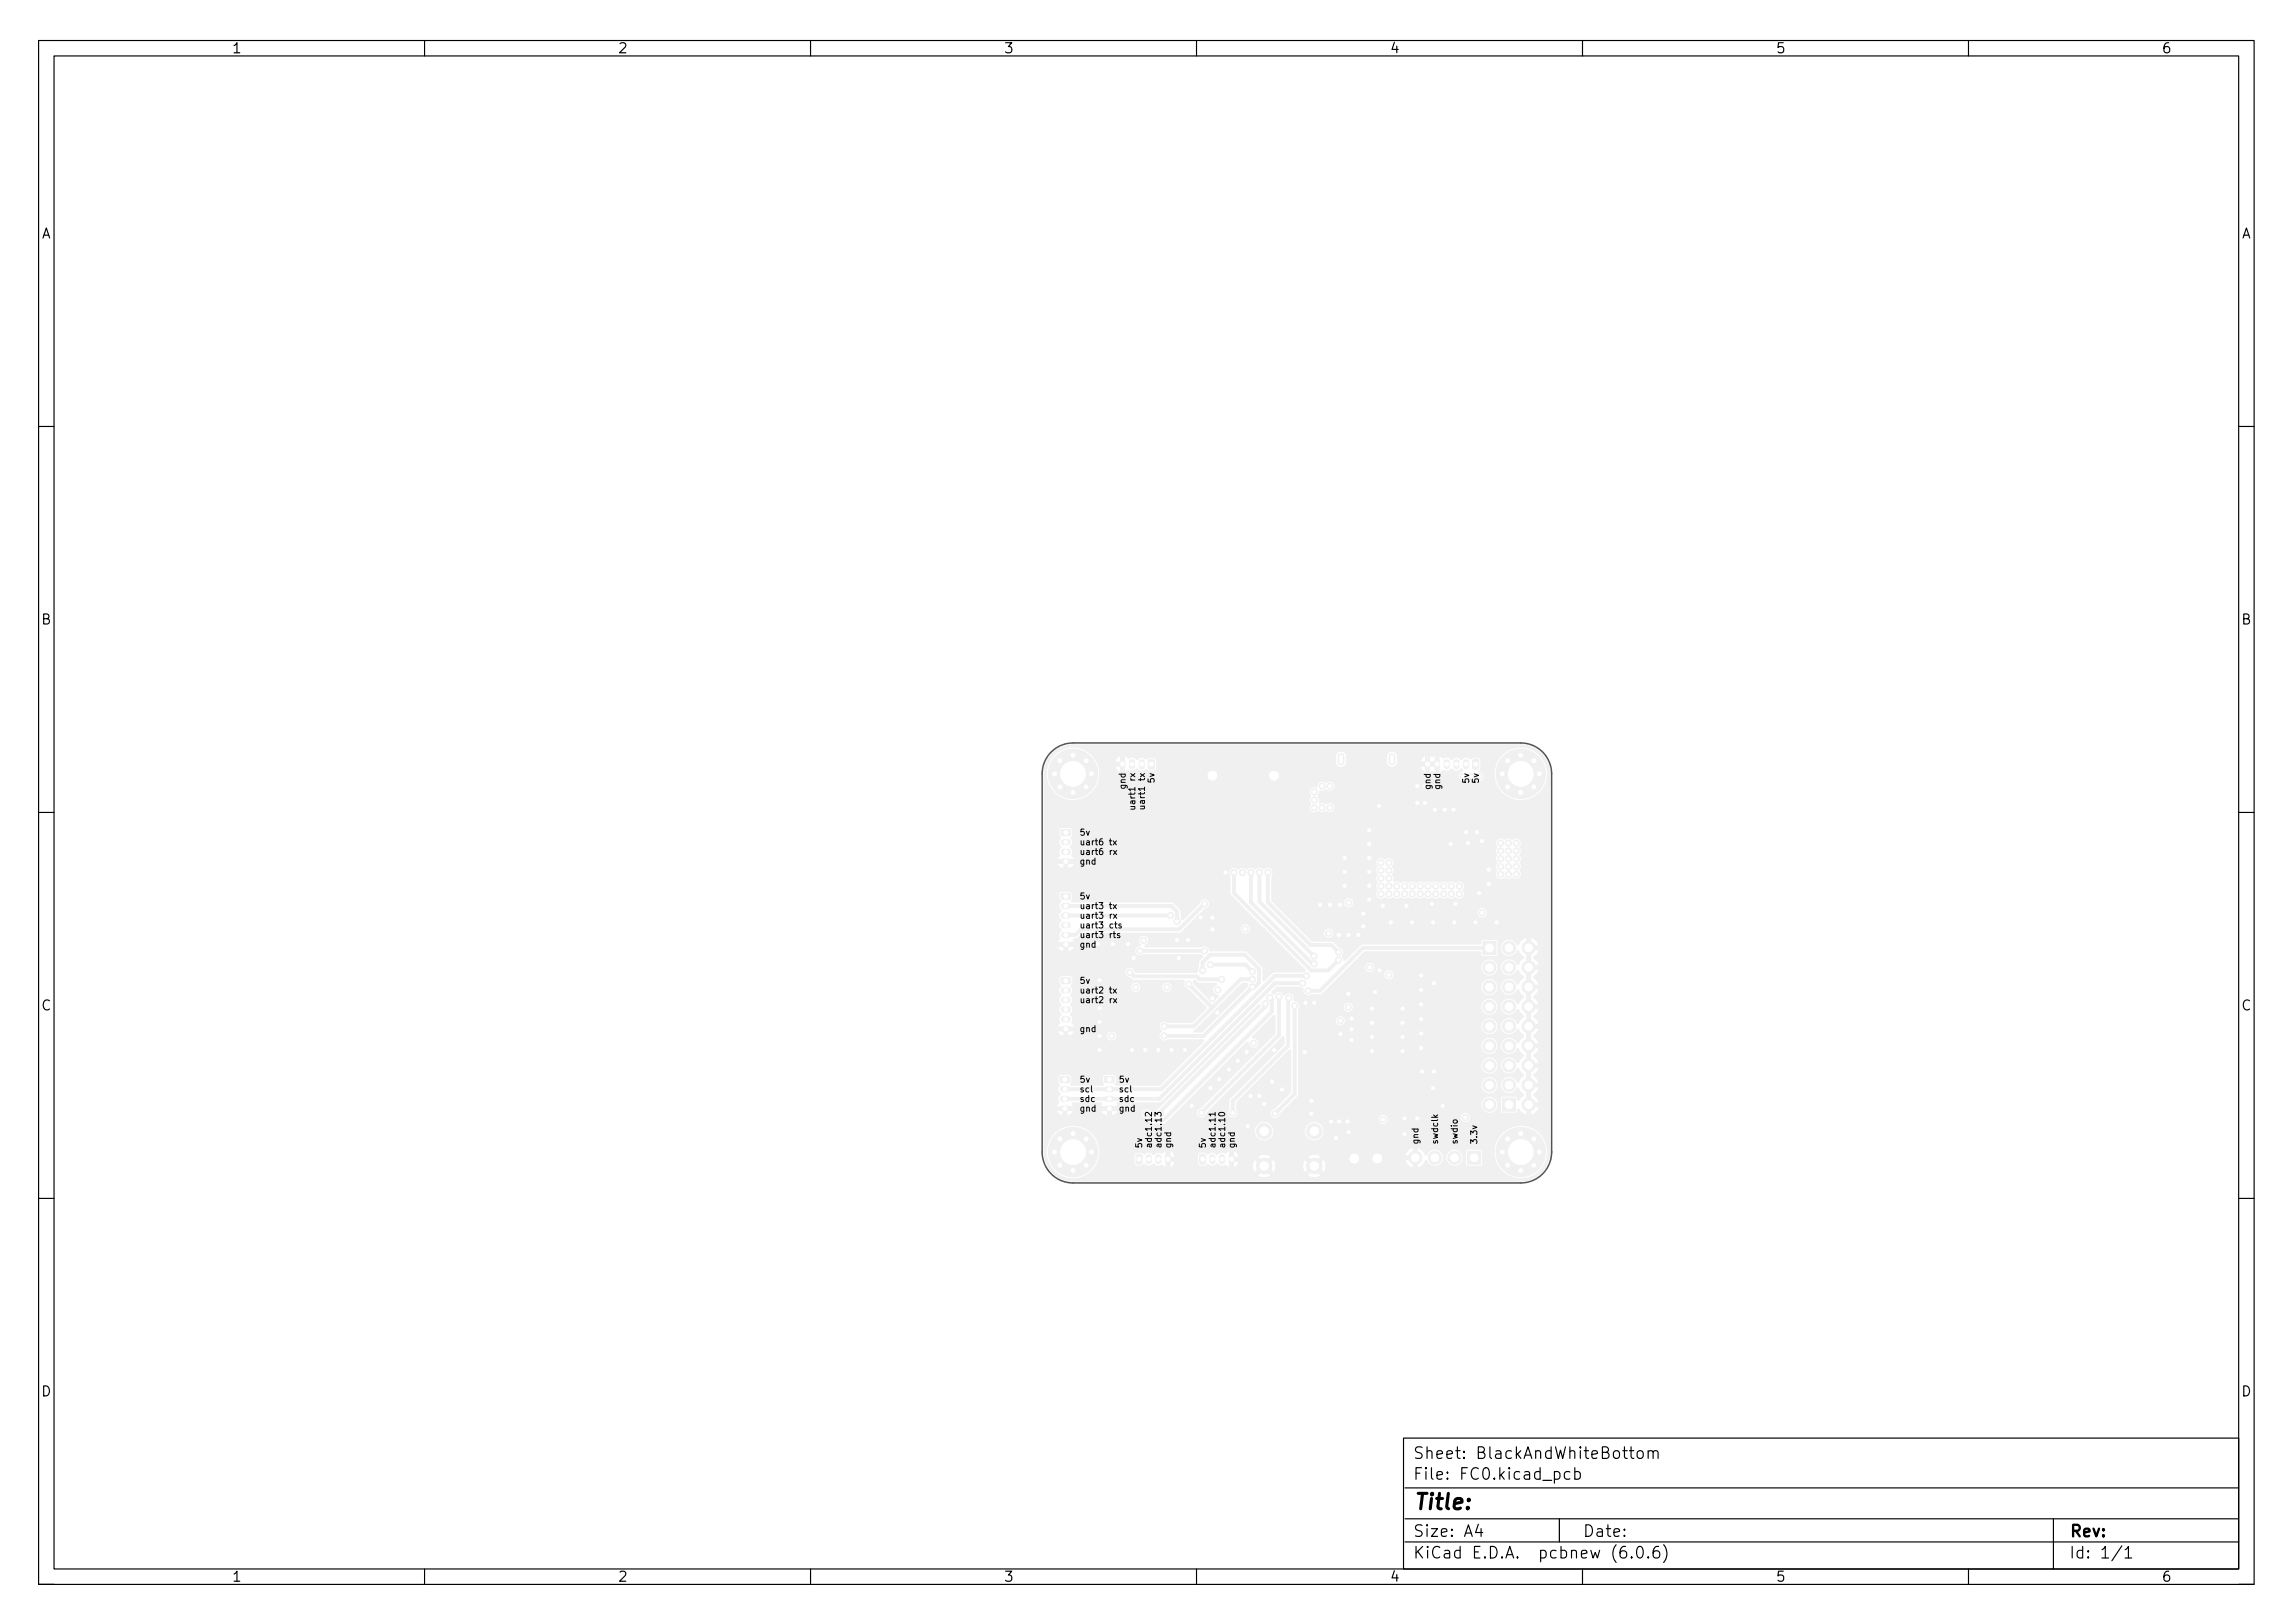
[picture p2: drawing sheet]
<svg xmlns="http://www.w3.org/2000/svg" width="297mm" height="210mm" viewBox="0 0 297 210" stroke-linecap="round" stroke-linejoin="round" font-family="sans-serif">
<defs><g id="words">
<text font-size="2.8" x="183" y="195.6">Title:</text>
<g font-size="2.1">
<text x="183" y="191.7">File: FC0.kicad_pcb</text>
<text x="183" y="189">Sheet: BlackAndWhiteBottom</text>
<text x="183" y="201.9">KiCad E.D.A. pcbnew (6.0.6)</text>
<text x="183" y="199.1">Size: A4</text>
<text x="205" y="199.1">Date:</text>
<text x="268" y="199.1">Rev:</text>
<text x="268" y="201.9">Id: 1/1</text>
</g>
<g font-size="1.8">
<text x="30" y="6.9">1</text>
<text x="80" y="6.9">2</text>
<text x="130" y="6.9">3</text>
<text x="180" y="6.9">4</text>
<text x="230" y="6.9">5</text>
<text x="280" y="6.9">6</text>
<text x="5.3" y="30.9">A</text>
<text x="290.3" y="30.9">A</text>
<text x="5.3" y="80.9">B</text>
<text x="290.3" y="80.9">B</text>
<text x="5.3" y="130.9">C</text>
<text x="290.3" y="130.9">C</text>
<text x="5.3" y="180.9">D</text>
<text x="290.3" y="180.9">D</text>
<text x="30" y="204.9">1</text>
<text x="80" y="204.9">2</text>
<text x="130" y="204.9">3</text>
<text x="180" y="204.9">4</text>
<text x="230" y="204.9">5</text>
<text x="280" y="204.9">6</text>
</g>
<g font-size="1.1">
<text x="149.6" y="101.6" transform="rotate(-90 149.6 101.6)">5v</text>
<text x="190.3" y="101.6" transform="rotate(-90 190.3 101.6)">5v</text>
<text x="191.6" y="101.6" transform="rotate(-90 191.6 101.6)">5v</text>
<text x="145.8" y="102.4" transform="rotate(-90 145.8 102.4)">gnd</text>
<text x="147.1" y="105.1" transform="rotate(-90 147.1 105.1)">uart1 rx</text>
<text x="148.3" y="105.1" transform="rotate(-90 148.3 105.1)">uart1 tx</text>
<text x="185.3" y="102.4" transform="rotate(-90 185.3 102.4)">gnd</text>
<text x="186.6" y="102.4" transform="rotate(-90 186.6 102.4)">gnd</text>
<text x="139.8" y="109.5">uart6 tx</text>
<text x="139.8" y="108.2">5v</text>
<text x="139.8" y="112">gnd</text>
<text x="139.8" y="110.7">uart6 rx</text>
<text x="139.8" y="119">uart3 rx</text>
<text x="139.8" y="117.8">uart3 tx</text>
<text x="139.8" y="116.5">5v</text>
<text x="139.8" y="120.3">uart3 cts</text>
<text x="139.8" y="121.5">uart3 rts</text>
<text x="139.8" y="122.8">gnd</text>
<text x="139.8" y="128.7">uart2 tx</text>
<text x="139.8" y="127.4">5v</text>
<text x="139.8" y="129.9">uart2 rx</text>
<text x="139.8" y="133.7">gnd</text>
<text x="139.8" y="140.3">5v</text>
<text x="139.8" y="141.5">scl</text>
<text x="139.8" y="142.8">sdc</text>
<text x="144.9" y="142.8">sdc</text>
<text x="144.9" y="141.5">scl</text>
<text x="144.9" y="140.3">5v</text>
<text x="139.8" y="144">gnd</text>
<text x="144.9" y="144">gnd</text>
<text x="148" y="148.8" transform="rotate(-90 148 148.8)">5v</text>
<text x="149.2" y="148.8" transform="rotate(-90 149.2 148.8)">adc1.12</text>
<text x="150.5" y="148.8" transform="rotate(-90 150.5 148.8)">adc1.13</text>
<text x="151.7" y="148.8" transform="rotate(-90 151.7 148.8)">gnd</text>
<text x="156.2" y="148.8" transform="rotate(-90 156.2 148.8)">5v</text>
<text x="157.4" y="148.8" transform="rotate(-90 157.4 148.8)">adc1.11</text>
<text x="158.7" y="148.8" transform="rotate(-90 158.7 148.8)">adc1.10</text>
<text x="159.9" y="148.8" transform="rotate(-90 159.9 148.8)">gnd</text>
<text x="183.7" y="148.3" transform="rotate(-90 183.7 148.3)">gnd</text>
<text x="186.3" y="148.3" transform="rotate(-90 186.3 148.3)">swdclk</text>
<text x="188.8" y="148.3" transform="rotate(-90 188.8 148.3)">swdio</text>
<text x="191.4" y="148.3" transform="rotate(-90 191.4 148.3)">3.3v</text>
</g>
</g></defs>
<g fill="none" stroke="#000" stroke-width=".15">
<path d="M5 5.2h287v200.1h-287zM7 7.2h283v196.1h-283zM55 5.2v2M105 5.2v2M155 5.2v2M205 5.2v2M255 5.2v2M5 55.2h2M290 55.2h2M5 105.2h2M290 105.2h2M5 155.2h2"/>
<path d="M290 155.2h2M181.8 186.3h108.2v17h-108.2zM182 199.8h108M182 196.8h108M182 192.8h108M191.5 197.5l-.4 1h1M191.9 198v1M202 196.8v3M203.4 190.7l-.5-.1-.3 .3v.4l.2 .3h.1h.5M204 190.7l.4-.1 .3 .3v.4l-.1 .3h-.2h-.4M204 190.1v1.5M211.1 187.9h.5"/>
<path d="M211.3 187.4v1.3l.1 .2h.2M212.2 188a.41 .41 0 0 1 .7 .2v.4a.41 .41 0 0 1-.4 .3 .41 .41 0 0 1-.4-.3v-.4zM213.5 188.1a.37 .37 0 0 1 .6 0v.8M213.5 187.9v1M214.1 188.1l.3-.2 .3 .1 .1 .9M266 196.8v6.5M5 205.2h2M55 203.3v2M105 203.3v2M155 203.3v2M205 203.3v2M211.4 201.7v.1h-.1l.1-.1v.1"/>
<path d="M212.2 200.4a.36 .36 0 0 1 .6 .2 .77 .77 0 0 1-.4 1.2 1 1 0 0 1-.2-1.4zM213.5 201.7l.1 .1h-.1h-.1l.1-.1v.1M214.9 200.3a.59 .59 0 0 0-.8 .7v.5l.2 .3h.4l.2-.1 .1-.5-.1-.2-.5-.1-.3 .3M215.5 200.1a1.72 1.72 0 0 1 0 2.3M255 203.3v2M274.9 200.3l-1.3 1.9M275.3 200.8l.4-.5v1.5M275.3 201.8h.8M290 205.2h2"/>
</g>
<g fill="#f0f0f0" stroke="#f0f0f0" stroke-width=".13">
<path d="M147.2 149.6l.6-.1 .1 .1 .1 1-.2 .2h-.4l-.2-.1z"/>
<path d="M155.5 149.6l.5-.1 .2 .1v1l-.1 .2h-.5l-.2-.1z"/>
<path d="M143.1 139.5h1.1l.2 .2-.1 .4-.1 .2-1-.1-.1-.1z"/>
<path d="M137.3 139.5h1.2l.1 .2v.4l-.2 .2-1-.1-.1-.1z"/>
<path d="M137.5 115.8l1.1-.1 .1 .2v.5l-.2 .1h-1l-.1-.2z"/>
<path d="M148.8 98.4l.6-.1 .1 .2 .1 .9-.2 .2h-.4l-.2-.1z"/>
<path d="M194.6 142.3h1.7v1.7h-1.7z"/>
<path d="M137.5 107.5h1.1l.1 .1v.5l-.2 .1h-1l-.1-.2z"/>
<path d="M137.5 126.7h1.1l.1 .1v.5l-.2 .1h-1l-.1-.2z"/>
<path d="M190.1 149.1h1.7v1.7h-1.7z"/>
<path d="M190.8 98.4l.6-.1 .1 .2 .1 .9-.2 .2h-.4l-.2-.1z"/>
<path d="M192.1 122h1.7v1.7h-1.7z"/>
<path d="M136.3 97.6a3.7 3.7 0 0 1 2.7-1.1h58a3.7 3.7 0 0 1 3.7 3.7h-.2l-.1-.7a3.5 3.5 0 0 0-3.9-2.7 3.5 3.5 0 0 0-2.9 3.8h-1.4a.75 .75 0 0 0-.5-.7l.1-.4v-1a.71 .71 0 0 0-.9-.4l-.3 .1a.28 .28 0 0 1-.4-.1 .72 .72 0 0 0-.9 .3 .79 .79 0 0 0-1.2 0 .84 .84 0 0 0-1-.2h-.2l-.5-.3v.8h-.5v-.8l-.4 .1-.3-.1v.8h-.5l-.1-.8a.9 .9 0 0 0-.6 .8l2.4 .1h-5.4v-.8a.71 .71 0 0 0-.7-.7 .71 .71 0 0 0-.7 .7v.8h-5.2v-.8a.71 .71 0 0 0-.7-.7 .71 .71 0 0 0-.7 .7v.5h-23.2a.68 .68 0 0 0-.9-.4l-.3 .1a.27 .27 0 0 1-.4-.1h-.5l-.5 .3-.4-.3-.6 .1-.5-.3v.8h-.5l-.1-.8a.9 .9 0 0 0-.6 .8h1.2v1.4h-.5l-.1-.8h-.6a.89 .89 0 0 0 .6 .8h.6l.3-.2a.33 .33 0 0 1 .5 0 .74 .74 0 0 0 .8-.3 .89 .89 0 0 0 1.2 .1h.1a.82 .82 0 0 0 .8 .2l.3-.1 .1-.3v-1h23.2a.74 .74 0 0 0 .8 .9l.4-.2 .2-.4h5.2a.71 .71 0 0 0 .7 .6 .71 .71 0 0 0 .7-.6h5.4v1.3h-.5v-.8h-.7v.8h-.5v-.8h-.7a.89 .89 0 0 0 .6 .8h.6l.3-.2 .4 .2 .7-.1a.37 .37 0 0 1 .5-.2l.1 .1a.72 .72 0 0 0 .8-.3 .81 .81 0 0 0 1.3 0l.2 .2-.4 .3-.2 .5h-23.1l-.2-.5a.71 .71 0 0 0-.8-.3 .71 .71 0 0 0-.5 .8h-6.5l-.2-.5a.71 .71 0 0 0-1.2 .1h-13.9l-.1-.7a3.5 3.5 0 0 0-5.6-2 3.5 3.5 0 0 0 .7 5.9 3.5 3.5 0 0 0 5-3.2l13.9 .1a.71 .71 0 0 0 .8 .9 .71 .71 0 0 0 .6-.6h6.5l.2 .3a.71 .71 0 0 0 .7 .3 .71 .71 0 0 0 .6-.6h23.1a.69 .69 0 0 0 .4 .6 .69 .69 0 0 0 .8-.2l.1 .1a.77 .77 0 0 0 .9-.1 .67 .67 0 0 0 .7 .2 .67 .67 0 0 0 .5-.6h1.3l.1 .8 .3 .6a3.5 3.5 0 0 0 3.9 1.6 3.5 3.5 0 0 0 2.6-3.4h.2v4.4h-27.8a.71 .71 0 0 0-.4-.6 .71 .71 0 0 0-.7 .2l-.5-.2h-.4v-.5l-.2-.4 .2-.6h.5l.4-.2a.68 .68 0 0 0 1 0 .68 .68 0 0 0-.1-1 .68 .68 0 0 0-.9 .1 .7 .7 0 0 0-.8-.1 .7 .7 0 0 0-.4 .6l-.1 .1a.69 .69 0 0 0-.8 .3 .69 .69 0 0 0 .1 .8v.1a.78 .78 0 0 0 0 1 .68 .68 0 0 0 0 .9 .68 .68 0 0 0 1 0l.1 .1a.77 .77 0 0 0 .9-.1 .68 .68 0 0 0 .7 .2 .68 .68 0 0 0 .4-.7h27.8v8.7h-3.6l-.2-.5 .2-.5-.2-.6 .2-.3-.1-.5a.4 .4 0 0 1 .1-.5v-.3l-.2-.3a.73 .73 0 0 0 .1-.8 .73 .73 0 0 0-.7-.4l-.4 .1-.4-.1-.6 .1a.74 .74 0 0 0-1.2 .5v.2a.45 .45 0 0 1 0 .7l.2 .7a.77 .77 0 0 0 0 1 .78 .78 0 0 0 0 1 .68 .68 0 0 0 .1 1 .68 .68 0 0 0 .9-.1l.1 .1a.77 .77 0 0 0 .9-.1 .67 .67 0 0 0 .8 .2 .67 .67 0 0 0 .4-.6h3.6v2.5h-11l-.1-.3a.4 .4 0 0 1 .1-.5 .7 .7 0 0 0-.4-.8 .7 .7 0 0 0-.8 .1 .74 .74 0 0 0-1 0h-.1a.74 .74 0 0 0-.9 0h-.1a.74 .74 0 0 0-.9 0h-.1a.74 .74 0 0 0-.9 0h-.1a.74 .74 0 0 0-1 0 .74 .74 0 0 0-1 0 .74 .74 0 0 0-1 0l-.2-.1h-.6l-.1-.1a.88 .88 0 0 0-.1-.8l.2-.5-.2-.6a.68 .68 0 0 0-.1-1 .68 .68 0 0 0-.9 .1 .7 .7 0 0 0-1 0h-39.2l-.4-.5a.74 .74 0 0 0-.1-1 .9 .9 0 0 0 0-1.3l.3-.4v-.5l-.2-.3-.2-.1h-1.1l-.2 .1-.1 .3v.5l.1 .3a.27 .27 0 0 1-.1 .4 .76 .76 0 0 0 .3 .9l-.2 .2a.85 .85 0 0 0 0 .9l-.4 .5h41.5l-.1 .3-.1 .3h-39.9v.6h-.5v-.6h-.9a.9 .9 0 0 0 .9 .6h.5a.89 .89 0 0 0 .9-.6h39.1a.45 .45 0 0 1 0 .7v.3l.1 .3a.9 .9 0 0 0 0 1.1v.1a1.25 1.25 0 0 0 0 1 .68 .68 0 0 0 .1 .9 .68 .68 0 0 0 .9 0l.2 .1a.77 .77 0 0 0 .8-.1l.2 .1a.77 .77 0 0 0 .8-.1l.2 .1a.77 .77 0 0 0 .9-.1l.1 .1a.77 .77 0 0 0 .9-.1l.1 .1a.77 .77 0 0 0 .9-.1l.1 .1a.77 .77 0 0 0 .9-.1l.1 .1a.77 .77 0 0 0 .9-.1l.2 .1a.77 .77 0 0 0 .8-.1l.2 .1a.77 .77 0 0 0 .9-.1 .67 .67 0 0 0 .7 .1 .67 .67 0 0 0 .4-.6h11v1.1h-25.3a.66 .66 0 0 0-1-.6 .66 .66 0 0 0 0 1.2 .66 .66 0 0 0 1-.5l25.3-.1v1.3h-8a.66 .66 0 0 0-1-.5 .66 .66 0 0 0-.1 1.1 .66 .66 0 0 0 1-.4l.1-.2h8v2.7h-27.9a.66 .66 0 0 0-1-.6 .66 .66 0 0 0-.1 1.1 .66 .66 0 0 0 1.1-.4v-.1h27.9v1.6h-1.3l-.1-.2a1.26 1.26 0 0 0-1-.8v1h2.4v2.6h-1.3l-.3-.6-.4-.4 .4-.5 .3-.6-1.1 .1v2h2.4v2.5h-1.3l-.3-.6-.4-.4 .4-.5 .3-.5h-1.1v2h2.4v2.5h-1.3l-.3-.5-.4-.5 .4-.4 .3-.6h-1.1v2h2.4v2.6h-1.3l-.3-.6-.4-.4 .4-.5 .3-.5h-1.1v2h2.4v2.5h-1.3l-.3-.6-.4-.4 .4-.5 .3-.5h-1.1v2h2.4v2.6h-1.3l-.3-.6-.4-.4 .4-.5 .3-.6-1.1 .1v2h2.4v2.5h-1.3l-.3-.6-.4-.4 .4-.5 .3-.5h-1.1v2h2.4v2.5h-1.3l-.3-.5-.4-.4v-.1l.5-.6 .1-.4h-1v2h2.4v.6h-2.4v1h-.5v-22.9a1.42 1.42 0 0 0-1.1 .9h-.1a1.14 1.14 0 0 0-1.8-.5h-.8l-.2-.2h-1.7l-.2 .2-.1 .3-.1 .1h-15.2l-.3 .2-1.9 1.9h-.2v-.1a.74 .74 0 0 1 0-.9v-.1a.71 .71 0 0 0-.7-.6l-.8-.8h-2.7l-5.1-5.2v-3.3a.68 .68 0 0 0-.2-.9 .68 .68 0 0 0-.9 .1 .78 .78 0 0 0-1.1 0 .78 .78 0 0 0-1.1 0 .78 .78 0 0 0-1.1 0 .68 .68 0 0 0-1-.1 .68 .68 0 0 0-.1 1l.1 2.3 1.1 1.3-3.8-.1a.67 .67 0 0 0-.7-.6 .67 .67 0 0 0-.7 .7l-2.1 2.1-.2-.3-.1-1-.8-.9-.3-.1h-12.9l-.1-.2 .2-.3v-.5a.45 .45 0 0 0-.4-.4h-1a.45 .45 0 0 0-.4 .4v.5l.1 .2a.28 .28 0 0 1-.1 .5 .76 .76 0 0 0 .3 .9 .81 .81 0 0 0 0 1.2 .76 .76 0 0 0-.1 1.2l.1 .1-.3 .5 .1 .6-.3 .5h2.2l-.2-.3 .1-.2 .5-.1 .7-.6h12.5l.3-.2 3-2.9 .4-.3 .2-.4h3.8l3.3 3.3h-1.8v-.1a.66 .66 0 0 0-1.1-.4 .66 .66 0 0 0 .2 1.1 .66 .66 0 0 0 .9-.6h1.8l5.2 5.2 .1 .2-.3 .1h-3.8l-1.2 1.1h-.1l-.1-.1-.1-1.6-2-2.1h-4.6l-.2-.1a.69 .69 0 0 0-1.1-.4h-7.2a.21 .21 0 0 1 .1-.3l.2-.3a.67 .67 0 0 0-.3-.8 .67 .67 0 0 0-.9 .2 .67 .67 0 0 0 .2 .9v.1l-.4 .1h-9v.7h-.5v-.7h-.9a.9 .9 0 0 0 .9 .7h.5a.89 .89 0 0 0 .9-.7h8.1a.67 .67 0 0 0-.2 1 .67 .67 0 0 0 1 .1h7.5l.2 .2-.5 .7v.7l-.2 .7h-8a.74 .74 0 0 0-1.1-.6l-.2 .2a.65 .65 0 0 0 .2 .9l.9 .5 6.5 .1-.1 .4 .2 .4h-1.7a.66 .66 0 0 0-.6-.7 .66 .66 0 0 0-.7 .7h-2.7a.66 .66 0 0 0-1-.6 .66 .66 0 0 0-.1 1.1 .66 .66 0 0 0 1.1-.4v-.1h2.7a.66 .66 0 0 0 .7 .7 .66 .66 0 0 0 .6-.7h1.7l.5 .3 2.3 2.4-1.8 1.8h-3.2a.67 .67 0 0 0-.8 0 .67 .67 0 0 0-.3 .6h-11l-.3-.4v-.2a.69 .69 0 0 0-.2-1 .82 .82 0 0 0 0-1.2 .82 .82 0 0 0 0-1.3 .88 .88 0 0 0 0-1.2l.3-.4v-.5l-.2-.3-.2-.1h-1l-.3 .1-.1 .3v.5l.2 .4a.79 .79 0 0 0 .1 1.2 .82 .82 0 0 0 0 1.2 .8 .8 0 0 0 0 1.3 .84 .84 0 0 0-.2 1v.1l-.4 .5h13.3l.3 .5-.4 .7h-5.4a.65 .65 0 0 0-.8-.6l-5.6-.1v.7h-.5v-.6h-.9a.9 .9 0 0 0 .9 .6h.5a.89 .89 0 0 0 .9-.6h4.7h-.1a.66 .66 0 0 0-.2 1.1 .66 .66 0 0 0 1.1-.5h5.4a.66 .66 0 0 0 .4 .6 .66 .66 0 0 0 .7-.1h4.6l.1 .2-5.6 5.7h-5.7a.34 .34 0 0 1 0-.5v-.5l-.2-.4h-1.2l-.3 .2-.1 .7a.29 .29 0 0 1 .1 .5h-4.1a.34 .34 0 0 1 0-.5v-.5l-.2-.4h-1.2l-.2 .1-.2 .3v.5l.3 .4-.1 .2a.7 .7 0 0 0 .1 1 .84 .84 0 0 0-.2 1l.1 .1-.4 .5h2.2l-.1-.3 .1-.1h3.6l.2 .1-.2 .3h2.2l-.1-.3 .1-.1 5.6-.1 12.7-12.6h.1v.2l-13.2 13.2-.3 .5v.4l-.2 .1-.3-.4a.68 .68 0 0 0-.5-.6 .68 .68 0 0 0-.7 .3h-4v.6h-.5l-.1-.6h-5.2v.6h-.5v-.6h-.9a.9 .9 0 0 0 .9 .6h.5a.89 .89 0 0 0 .9-.6h3.5a.9 .9 0 0 0 .8 .6h.6a.89 .89 0 0 0 .8-.6h3.2h-.1a.69 .69 0 0 0 .6 1.1l.7 .6h1.5l.3-.1 10.5-10.5 .2 .1a.67 .67 0 0 0 .7 .7 .67 .67 0 0 0 .7-.7 .67 .67 0 0 0-.8-.6v-.2l2.7-2.7h.2l-.1 2.3-9.6 9.6a.67 .67 0 0 0-.5 .7 .67 .67 0 0 0 .7 .6 .67 .67 0 0 0 .6-.6l9.8-9.8a.13 .13 0 0 1 .2-.1 .13 .13 0 0 1 .1 .1l-.1 .9-7 7.1-.1 1.3a.67 .67 0 0 0 0 .9 .67 .67 0 0 0 1 0 .67 .67 0 0 0 0-.9v-.9l6.8-6.8h.1l.1 .1v5.4l-2.1 2.1a.67 .67 0 0 0-.6 .7 .67 .67 0 0 0 .7 .6 .67 .67 0 0 0 .7-.6l2.2-2.2 .1-.3v-11.1a.69 .69 0 0 0 .1-.8 .69 .69 0 0 0-.7-.3 .72 .72 0 0 0-.2-.8 .72 .72 0 0 0-.8-.1l-.3 .2a.75 .75 0 0 0-1.3-.1l-.2-.3 .6-.6h2.9l.5 .2v.1a.66 .66 0 0 0 .3 .7 .66 .66 0 0 0 .7 0l1.5-.1 5.5-5.5h14.9l.1 .1 .1 .4 .1 .1h1.8l.2-.2v-1.8h.8l-.4 .5v.6l.3 .6 .5 .3a1.16 1.16 0 0 0 1.4-.8l.1 .1 .3 .5 .4 .3-.5 .5-.2 .4h-.2a1.11 1.11 0 0 0-1.2-.7 1.11 1.11 0 0 0-.9 1.1h-.3l-.1-.2a1.11 1.11 0 0 0-1.2-.9 1.11 1.11 0 0 0-1 1.1h-13.7a.66 .66 0 0 0-1-.6 .66 .66 0 0 0 0 1.1 .66 .66 0 0 0 1-.4l13.7-.1 .1 .5 .5 .5h-11.8a.66 .66 0 0 0-1-.6 .66 .66 0 0 0 0 1.1 .66 .66 0 0 0 1-.5h11.8l.3 .1h.4l.4-.1 .3-.2 .2-.4 .1-.4h.3l.1 .5 .2 .3 .6 .3a1.09 1.09 0 0 0 1.2-.7h.2l.3 .5 .4 .4-.5 .4-.2 .5-.2-.1a1.11 1.11 0 0 0-1.1-.6 1.11 1.11 0 0 0-1 .9v.2h-.3a1.11 1.11 0 0 0-1.4-1.1 1.11 1.11 0 0 0-.7 1.6 1.11 1.11 0 0 0 1.6 .4l.3-.4 .2-.5h.3l.1 .4 .4 .5 .5 .2 .6-.2 .6-.6 .8 .9-.5 .5-.2 .4h-.1a1.13 1.13 0 0 0-1.3-.7 1.13 1.13 0 0 0-.9 1.1h-.3l-.1-.2a1.11 1.11 0 0 0-1.2-.9 1.11 1.11 0 0 0-1 1.2h-16.5a.66 .66 0 0 0-.9-.6 .66 .66 0 0 0-.1 1.1 .66 .66 0 0 0 1-.5h16.5l.2 .6 .5 .3a1.11 1.11 0 0 0 1.3-.3l.2-.3 .1-.4h.3l.2 .6 .3 .3 .3 .2h.4l.4-.1 .6-.6h.1l.3 .5 .4 .4-.5 .4-.2 .5h-.1a1.13 1.13 0 0 0-1.3-.8 1.13 1.13 0 0 0-.9 1.1h-.3l-.1-.2a1.11 1.11 0 0 0-.8-.8 1.11 1.11 0 0 0-1.1 .3h-17.8a.66 .66 0 0 0-1-.6 .66 .66 0 0 0 0 1.2 .66 .66 0 0 0 1-.5l17.8-.1a1.11 1.11 0 0 0-.2 1.2 1.11 1.11 0 0 0 1.2 .7l.4-.2 .3-.2 .2-.4 .1-.4h.3l.1 .5 .4 .5 .5 .2 .6-.2 .6-.6 .8 .9-.5 .5-.2 .4h-.1a1.13 1.13 0 0 0-1.3-.7 1.13 1.13 0 0 0-.9 1.1h-.3l-.1-.2a1.11 1.11 0 0 0-1.7-.7 1.11 1.11 0 0 0 .2 1.9 1.11 1.11 0 0 0 1.6-1h.3l.2 .6 .4 .4a1.15 1.15 0 0 0 1.6-.7l.1 .1 .3 .5 .4 .3-.5 .5-.2 .4h-.2a1.11 1.11 0 0 0-1.2-.7 1.11 1.11 0 0 0-.9 1.1h-.3l-.1-.2a1.11 1.11 0 0 0-1.7-.6 1.11 1.11 0 0 0 .2 1.8 1.11 1.11 0 0 0 1.6-1h.3l.1 .5a1.14 1.14 0 0 0 1 .6 1.14 1.14 0 0 0 1.1-.7h.1l.3 .5 .4 .4-.5 .4-.2 .5-.2-.1a1.11 1.11 0 0 0-1.2-.6 1.11 1.11 0 0 0-.9 1.1h-.3l-.1-.2a1.11 1.11 0 0 0-1.7-.7 1.11 1.11 0 0 0 .2 1.9 1.11 1.11 0 0 0 1.6-1h.3l.1 .4a1.14 1.14 0 0 0 1 .7 1.14 1.14 0 0 0 1.1-.8h.1l.3 .5 .4 .4-.6 .7h-.2v-.3l-.2-.2h-1.8l-.2 .2v.9h-.3l-.1-.2a1.11 1.11 0 0 0-1.8-.6 1.11 1.11 0 0 0 .3 1.8l.2 .1a1.11 1.11 0 0 0 .9-.2l.3-.3 .2-.6h.3v.9l.1 .2h1.9l.3-.5 .4 .4 .4 .3h.8a1.28 1.28 0 0 0 1.1-1h1.3v1.4l-10.2-.1a.66 .66 0 0 0-.8-.6 .66 .66 0 0 0-.5 .9h-9.4a.66 .66 0 0 0-1-.4 .66 .66 0 0 0 .1 1.1 .66 .66 0 0 0 .9-.7h9.4v.1a.66 .66 0 0 0 .8 .3 .66 .66 0 0 0 .5-.6h10.2v4.4h-.2l-.1-.3a3.5 3.5 0 0 0-5.6-2.3h-23.3v-.3a1.26 1.26 0 0 0-1.4-1 1.26 1.26 0 0 0-1.1 1.3h-4v-.3a1.26 1.26 0 0 0-2-.8 1.26 1.26 0 0 0 .2 2.2 1.26 1.26 0 0 0 1.8-1.1h4v.2a1.26 1.26 0 0 0 1.4 1 1.26 1.26 0 0 0 1.1-1.2h23.3l-.6 .6a3.4 3.4 0 0 0-.6 1.9h-1.5l-.3-.2h-1.7l-.2 .1v1h-.4v-.2a1.11 1.11 0 0 0-1.2-.9 1.11 1.11 0 0 0-1 1.1h-.3v-.2a1.14 1.14 0 0 0-1.1-.9 1.14 1.14 0 0 0-1.1 .7h-.1a1.39 1.39 0 0 0-1.1-.9v1h-.5v-1a1.28 1.28 0 0 0-1.1 1h1.6v.5h-4.5v-.2a.71 .71 0 0 0-.8-.6 .71 .71 0 0 0-.6 .8h-1.6v-.2a.71 .71 0 0 0-.5-.6 .71 .71 0 0 0-.8 .3v.1h-3.7a1.49 1.49 0 0 0-1.7 0h-4.8a1.45 1.45 0 0 0-1.7 0l.1 .1h-2.5a.89 .89 0 0 0-.7-.9v.9h3.2l.8 .8 .8-.9h4.8l.9 .9 .8-.9h3.7l-.1 .2a.71 .71 0 0 0 .7 .8 .71 .71 0 0 0 .7-.6h1.6l.1 .3a.71 .71 0 0 0 .8 .3 .71 .71 0 0 0 .5-.6h4.5v1.1h-.5v-1.1h-1.1l.2 .5 .3 .4h-10.7l-.1-.5-.2-.4-.9 .9h-.7l-.9-.9-.2 .4-.1 .5h-3.4l-.1-.5-.2-.4-.9 .9h-.7l-.9-.9-.1 .3-2.6-.1v.9h-.5v-2.3l-.4 .2a.33 .33 0 0 1-.5 .1 .79 .79 0 0 0-.7 .3 .88 .88 0 0 0-1.3-.1l-.1-.1a.84 .84 0 0 0-.8-.1l-.3 .2-.1 .4h-2.9a.89 .89 0 0 0-.6-.9v.9h3.5v.6l-3.5-.1v.9h-.6v-2.3l-.3 .2h-8.2a3.5 3.5 0 0 0-5.1-3 3.5 3.5 0 0 0-.3 5.9 3.5 3.5 0 0 0 5.3-2.5l.1-.4h8.2l-.2 .2a.74 .74 0 0 0-1 .2l-.2-.1a.68 .68 0 0 0-1 0l-.5-.2h-.2a.53 .53 0 0 0-.7 .3v1.2a.77 .77 0 0 0 .9 .3l.3-.2a.27 .27 0 0 1 .4 .1h.1a.72 .72 0 0 0 .8-.2 .84 .84 0 0 0 1 .2l.1-.1 .5 .4h.6l.4-.3 .2-.5h2.9a.51 .51 0 0 0 .4 .6h.6l.2-.2a.27 .27 0 0 1 .5 .1h.1a.72 .72 0 0 0 .7-.2 .84 .84 0 0 0 1.1 .2l.1-.1 .5 .4h.5l.5-.3 .2-.5h1.9l-.1 .8 .2 .6 .9-.8h.7l.9 .8 .2-.4 .1-.4h3.4l.1 .4 .2 .4 .9-.8h.7l.9 .8 .2-.4 .1-.4h10.7l.5 .2h.6a1.38 1.38 0 0 0 1.1-.9h.1l.4 .5 .5 .2a1.1 1.1 0 0 0 1.1-.6l.2-.5h.3l.1 .4 .2 .4 .6 .3a1.1 1.1 0 0 0 1.2-.6l.1-.5h.4v.9l.1 .2h1.9l.2-.2v-1.8h1.5v.5a3.4 3.4 0 0 0 1.8 2.7h-24.3l-.8-.9-.9 .9h-4.8l-.8-.9-.9 .9a1.46 1.46 0 0 0 1.7 0h4.8a1.49 1.49 0 0 0 1.7 0h24.3a3.5 3.5 0 0 0 5.1-3.1h.2v.8a3.8 3.8 0 0 1-3.7 3h-58a3.7 3.7 0 0 1-3.7-3.7v-49.1a3.7 3.7 0 0 1 1-2.6z"/>
<path d="M154.7 133.5l.3-.2 5.9-5.9h.7v.4l-5.9 5.9h-.9l-.1-.1z"/>
<path d="M154.6 127h.2l.5 .4h2.2l.1 .1-.1 .1a.67 .67 0 0 0-.4 .8 .67 .67 0 0 0 .7 .5v.2l-.7 .6h-.1l-2.3-2.2-.1-.4z"/>
<circle cx="136.6" cy="149.2" r=".4"/>
<circle cx="137.3" cy="150.9" r=".4"/>
<circle cx="141.4" cy="149.2" r=".4"/>
<circle cx="139" cy="146.8" r=".4"/>
<circle cx="137.3" cy="147.6" r=".4"/>
<circle cx="139" cy="151.6" r=".4"/>
<circle cx="140.7" cy="150.9" r=".4"/>
<circle cx="139" cy="149.2" r="3.2"/>
<circle cx="140.7" cy="147.6" r=".4"/>
<circle cx="170.3" cy="151.1" r="1"/>
<circle cx="163.8" cy="151.1" r="1"/>
<circle cx="170.3" cy="146.6" r="1"/>
<circle cx="163.8" cy="146.6" r="1"/>
<circle cx="198" cy="143.1" r=".85"/>
<circle cx="195.5" cy="140.6" r=".85"/>
<circle cx="198" cy="140.6" r=".85"/>
<circle cx="195.5" cy="138" r=".85"/>
<circle cx="198" cy="138" r=".85"/>
<circle cx="195.5" cy="135.5" r=".85"/>
<circle cx="198" cy="135.5" r=".85"/>
<circle cx="195.5" cy="132.9" r=".85"/>
<circle cx="198" cy="132.9" r=".85"/>
<circle cx="195.5" cy="130.4" r=".85"/>
<circle cx="198" cy="130.4" r=".85"/>
<circle cx="195.5" cy="127.9" r=".85"/>
<circle cx="198" cy="127.9" r=".85"/>
<circle cx="195.5" cy="125.3" r=".85"/>
<circle cx="198" cy="125.3" r=".85"/>
<circle cx="195.5" cy="122.8" r=".85"/>
<circle cx="198" cy="122.8" r=".85"/>
<circle cx="195.3" cy="98.6" r=".4"/>
<circle cx="197" cy="102.6" r=".4"/>
<circle cx="197" cy="97.8" r=".4"/>
<circle cx="198.7" cy="98.6" r=".4"/>
<circle cx="198.7" cy="101.9" r=".4"/>
<circle cx="197" cy="100.2" r="3.2"/>
<circle cx="194.6" cy="100.2" r=".4"/>
<circle cx="199.4" cy="100.2" r=".4"/>
<circle cx="195.3" cy="101.9" r=".4"/>
<circle cx="197" cy="149.2" r="3.2"/>
<circle cx="197" cy="151.6" r=".4"/>
<circle cx="194.6" cy="149.2" r=".4"/>
<circle cx="195.3" cy="150.9" r=".4"/>
<circle cx="198.7" cy="150.9" r=".4"/>
<circle cx="195.3" cy="147.6" r=".4"/>
<circle cx="199.4" cy="149.2" r=".4"/>
<circle cx="197" cy="146.8" r=".4"/>
<circle cx="198.7" cy="147.6" r=".4"/>
<circle cx="188.4" cy="150" r=".85"/>
<circle cx="185.9" cy="150" r=".85"/>
<circle cx="183.3" cy="150" r=".85"/>
<circle cx="192.9" cy="125.3" r=".85"/>
<circle cx="192.9" cy="127.9" r=".85"/>
<circle cx="192.9" cy="130.4" r=".85"/>
<circle cx="192.9" cy="133" r=".85"/>
<circle cx="192.9" cy="135.5" r=".85"/>
<circle cx="192.9" cy="138" r=".85"/>
<circle cx="192.9" cy="140.6" r=".85"/>
<circle cx="192.9" cy="143.1" r=".85"/>
<circle cx="136.6" cy="100.2" r=".4"/>
<circle cx="141.4" cy="100.2" r=".4"/>
<circle cx="137.3" cy="98.6" r=".4"/>
<circle cx="140.7" cy="101.9" r=".4"/>
<circle cx="139" cy="97.8" r=".4"/>
<circle cx="140.7" cy="98.6" r=".4"/>
<circle cx="139" cy="102.6" r=".4"/>
<circle cx="137.3" cy="101.9" r=".4"/>
<circle cx="139" cy="100.2" r="3.2"/>
<circle cx="191.1" cy="119.5" r=".4"/>
<circle cx="163.8" cy="143" r=".4"/>
<circle cx="146.6" cy="136" r=".4"/>
<circle cx="185.5" cy="117.1" r=".4"/>
<circle cx="176" cy="121.1" r=".4"/>
<circle cx="184.1" cy="128.2" r=".4"/>
<circle cx="171" cy="117.2" r=".4"/>
<circle cx="186.9" cy="143.3" r=".4"/>
<circle cx="181.7" cy="136.2" r=".4"/>
<circle cx="184.1" cy="132" r=".4"/>
<circle cx="177.7" cy="134.3" r=".4"/>
<circle cx="191.3" cy="107.8" r=".4"/>
<circle cx="174.7" cy="128.8" r=".4"/>
<circle cx="181.9" cy="144.9" r=".4"/>
<circle cx="142.4" cy="127" r=".4"/>
<circle cx="160.4" cy="137.4" r=".4"/>
<circle cx="181.7" cy="134.3" r=".4"/>
<circle cx="183.6" cy="144.9" r=".4"/>
<circle cx="179.1" cy="117.3" r=".4"/>
<circle cx="187.9" cy="109.3" r=".4"/>
<circle cx="184.1" cy="130.1" r=".4"/>
<circle cx="174.6" cy="145.3" r=".4"/>
<circle cx="164.8" cy="140.1" r=".4"/>
<circle cx="177.7" cy="136.2" r=".4"/>
<circle cx="173.6" cy="134" r=".4"/>
<circle cx="142.4" cy="128.8" r=".4"/>
<circle cx="146.1" cy="122.3" r=".4"/>
<circle cx="166.1" cy="141.1" r=".4"/>
<circle cx="163.1" cy="142" r=".4"/>
<circle cx="188.5" cy="117.1" r=".4"/>
<circle cx="177.4" cy="111.2" r=".4"/>
<circle cx="182.9" cy="119.5" r=".4"/>
<circle cx="162" cy="142" r=".4"/>
<circle cx="158.7" cy="113" r=".4"/>
<circle cx="157.7" cy="131.2" r=".4"/>
<circle cx="177.7" cy="132.5" r=".4"/>
<circle cx="169" cy="136.3" r=".4"/>
<circle cx="192.9" cy="112.6" r=".4"/>
<circle cx="157" cy="118.9" r=".4"/>
<circle cx="157.9" cy="139.8" r=".4"/>
<circle cx="170.3" cy="129.9" r=".4"/>
<circle cx="142.4" cy="136" r=".4"/>
<circle cx="146.9" cy="124.1" r=".4"/>
<circle cx="185.8" cy="138.8" r=".4"/>
<circle cx="174.2" cy="111.1" r=".4"/>
<circle cx="161.5" cy="136.3" r=".4"/>
<circle cx="174.7" cy="121.1" r=".4"/>
<circle cx="172.3" cy="117.2" r=".4"/>
<circle cx="182.2" cy="117.3" r=".4"/>
<circle cx="172.4" cy="145.3" r=".4"/>
<circle cx="178.6" cy="104.4" r=".4"/>
<circle cx="178.1" cy="128.5" r=".4"/>
<circle cx="184.1" cy="135.8" r=".4"/>
<circle cx="154.4" cy="143.3" r=".4"/>
<circle cx="175.1" cy="134.7" r=".4"/>
<circle cx="177.7" cy="130.7" r=".4"/>
<circle cx="176.6" cy="118.4" r=".4"/>
<circle cx="161.6" cy="145.9" r=".4"/>
<circle cx="175.1" cy="133.3" r=".4"/>
<circle cx="175.1" cy="131.9" r=".4"/>
<circle cx="184.1" cy="133.9" r=".4"/>
<circle cx="190.2" cy="109.2" r=".4"/>
<circle cx="148.3" cy="136" r=".4"/>
<circle cx="169.9" cy="144.3" r=".4"/>
<circle cx="174.2" cy="114.7" r=".4"/>
<circle cx="177.4" cy="116.5" r=".4"/>
<circle cx="192" cy="109" r=".4"/>
<circle cx="185.8" cy="127.4" r=".4"/>
<circle cx="183.6" cy="101.8" r=".4"/>
<circle cx="189.9" cy="107.8" r=".4"/>
<circle cx="188.4" cy="119.5" r=".4"/>
<circle cx="173.1" cy="147.4" r=".4"/>
<circle cx="142.4" cy="134.2" r=".4"/>
<circle cx="159.2" cy="138.6" r=".4"/>
<circle cx="142.4" cy="130.6" r=".4"/>
<circle cx="142.4" cy="132.4" r=".4"/>
<circle cx="184.1" cy="126.4" r=".4"/>
<circle cx="188.3" cy="104.9" r=".4"/>
<circle cx="153.5" cy="136" r=".4"/>
<circle cx="173.4" cy="121.1" r=".4"/>
<circle cx="191.6" cy="115.7" r=".4"/>
<circle cx="169.9" cy="142.6" r=".4"/>
<circle cx="173.6" cy="117.2" r=".4"/>
<circle cx="177.4" cy="107.6" r=".4"/>
<circle cx="185.9" cy="104.9" r=".4"/>
<circle cx="157" cy="129.3" r=".4"/>
<circle cx="156.8" cy="141" r=".4"/>
<circle cx="150.1" cy="136" r=".4"/>
<circle cx="187.1" cy="104.9" r=".4"/>
<circle cx="178.7" cy="125.7" r=".4"/>
<circle cx="142.2" cy="122.3" r=".4"/>
<circle cx="181.9" cy="146.9" r=".4"/>
<circle cx="192.9" cy="114.5" r=".4"/>
<circle cx="185.6" cy="141" r=".4"/>
<circle cx="173.5" cy="145.3" r=".4"/>
<circle cx="153.9" cy="121.8" r=".4"/>
<circle cx="177.4" cy="109.4" r=".4"/>
<circle cx="174.7" cy="146.7" r=".4"/>
<circle cx="169.1" cy="129.9" r=".4"/>
<circle cx="152.7" cy="124.1" r=".4"/>
<circle cx="176.6" cy="120" r=".4"/>
<circle cx="155.5" cy="118.9" r=".4"/>
<circle cx="144.2" cy="122.3" r=".4"/>
<circle cx="183.6" cy="104" r=".4"/>
<circle cx="184.6" cy="104" r=".4"/>
<circle cx="185.6" cy="119.5" r=".4"/>
<circle cx="181.7" cy="130.7" r=".4"/>
<circle cx="181.7" cy="132.5" r=".4"/>
<circle cx="174.2" cy="113" r=".4"/>
<circle cx="151.8" cy="136" r=".4"/>
<circle cx="165.1" cy="136" r=".4"/>
<circle cx="177.4" cy="113" r=".4"/>
<circle cx="193.9" cy="119.5" r=".4"/>
<circle cx="180.2" cy="119.5" r=".4"/>
<circle cx="184.2" cy="138.8" r=".4"/>
<circle cx="177.4" cy="114.7" r=".4"/>
<circle cx="152.5" cy="121.8" r=".4"/>
<circle cx="157" cy="120.4" r=".4"/>
<circle cx="179.9" cy="112.8" r=".4"/>
<circle cx="172.1" cy="120.9" r=".4"/>
<circle cx="178.9" cy="112.8" r=".4"/>
<circle cx="178.9" cy="114.8" r=".4"/>
<circle cx="177.4" cy="125.3" r=".4"/>
<circle cx="189.8" cy="144.8" r=".4"/>
<circle cx="162.4" cy="135.1" r=".4"/>
<circle cx="189.1" cy="114.8" r=".4"/>
<circle cx="179.9" cy="113.8" r=".4"/>
<circle cx="187" cy="115.8" r=".4"/>
<circle cx="179.9" cy="126.3" r=".4"/>
<circle cx="185" cy="114.8" r=".4"/>
<circle cx="173.6" cy="132.2" r=".4"/>
<circle cx="184" cy="114.8" r=".4"/>
<circle cx="185" cy="115.8" r=".4"/>
<circle cx="188" cy="114.8" r=".4"/>
<circle cx="160.9" cy="113" r=".4"/>
<circle cx="157.8" cy="128.2" r=".4"/>
<circle cx="147.1" cy="127.9" r=".4"/>
<circle cx="186" cy="115.8" r=".4"/>
<circle cx="144" cy="134.2" r=".4"/>
<circle cx="180.9" cy="115.8" r=".4"/>
<circle cx="183" cy="114.8" r=".4"/>
<circle cx="179.9" cy="111.8" r=".4"/>
<circle cx="148.1" cy="121.8" r=".4"/>
<circle cx="178.9" cy="111.8" r=".4"/>
<circle cx="179.9" cy="115.8" r=".4"/>
<circle cx="174.7" cy="130.5" r=".4"/>
<circle cx="179.2" cy="145" r=".4"/>
<circle cx="174.7" cy="116.9" r=".4"/>
<circle cx="186" cy="114.8" r=".4"/>
<circle cx="181.9" cy="114.8" r=".4"/>
<circle cx="183" cy="115.8" r=".4"/>
<circle cx="180.9" cy="114.8" r=".4"/>
<circle cx="178.9" cy="115.8" r=".4"/>
<circle cx="188" cy="115.8" r=".4"/>
<circle cx="161.3" cy="120.4" r=".4"/>
<circle cx="181.9" cy="115.8" r=".4"/>
<circle cx="184" cy="115.8" r=".4"/>
<circle cx="187" cy="114.8" r=".4"/>
<circle cx="151.2" cy="127.9" r=".4"/>
<circle cx="189.1" cy="115.8" r=".4"/>
<circle cx="178.9" cy="113.8" r=".4"/>
<circle cx="179.9" cy="114.8" r=".4"/>
<circle cx="165.2" cy="144.3" r=".4"/>
<circle cx="167.7" cy="130.3" r=".4"/>
<circle cx="195.4" cy="113.3" r=".4"/>
<circle cx="196.4" cy="109.2" r=".4"/>
<circle cx="194.4" cy="111.2" r=".4"/>
<circle cx="192" cy="118.2" r=".4"/>
<circle cx="195.4" cy="109.2" r=".4"/>
<circle cx="194.4" cy="110.2" r=".4"/>
<circle cx="195.4" cy="111.2" r=".4"/>
<circle cx="196.4" cy="110.2" r=".4"/>
<circle cx="195.4" cy="112.3" r=".4"/>
<circle cx="196.4" cy="113.3" r=".4"/>
<circle cx="194.4" cy="112.3" r=".4"/>
<circle cx="194.4" cy="109.2" r=".4"/>
<circle cx="196.4" cy="111.2" r=".4"/>
<circle cx="196.4" cy="112.3" r=".4"/>
<circle cx="194.4" cy="113.3" r=".4"/>
<circle cx="195.4" cy="110.2" r=".4"/>
<circle cx="170.3" cy="104.6" r=".4"/>
<circle cx="170.3" cy="102.6" r=".4"/>
<circle cx="171.3" cy="101.8" r=".4"/>
<circle cx="172.3" cy="104.6" r=".4"/>
<circle cx="170.3" cy="103.6" r=".4"/>
<circle cx="171.3" cy="104.6" r=".4"/>
<circle cx="190.6" cy="100.6" r=".4"/>
<circle cx="172.3" cy="101.8" r=".4"/>
<circle cx="191.6" cy="100.6" r=".4"/>
<circle cx="164.2" cy="113" r=".4"/>
<circle cx="173.4" cy="123.4" r=".4"/>
<circle cx="163.1" cy="113" r=".4"/>
<circle cx="170.2" cy="123.9" r=".4"/>
<circle cx="162" cy="113" r=".4"/>
<circle cx="170.2" cy="124.9" r=".4"/>
<circle cx="173.4" cy="124.4" r=".4"/>
<circle cx="159.8" cy="113" r=".4"/>
<circle cx="169.4" cy="128.4" r=".4"/>
<circle cx="152.5" cy="119.4" r=".4"/>
<circle cx="151.6" cy="118.6" r=".4"/>
<circle cx="156" cy="117.1" r=".4"/>
<circle cx="169.2" cy="126.4" r=".4"/>
<circle cx="168.7" cy="127.4" r=".4"/>
<circle cx="155.6" cy="144.2" r=".4"/>
<circle cx="165.7" cy="129.1" r=".4"/>
<circle cx="159.7" cy="144.2" r=".4"/>
<circle cx="167" cy="129.3" r=".4"/>
<circle cx="148.5" cy="144.3" r=".4"/>
<circle cx="164.5" cy="129.2" r=".4"/>
<circle cx="163.9" cy="130" r=".4"/>
<circle cx="150.4" cy="144.3" r=".4"/>
<circle cx="158.2" cy="126.9" r=".4"/>
<circle cx="146.4" cy="126" r=".4"/>
<circle cx="156" cy="123.2" r=".4"/>
<circle cx="147.7" cy="123.2" r=".4"/>
<circle cx="150.8" cy="134.2" r=".4"/>
<circle cx="162.2" cy="127.9" r=".4"/>
<circle cx="155.8" cy="125.7" r=".4"/>
<circle cx="162.2" cy="126.9" r=".4"/>
<circle cx="154" cy="127.5" r=".4"/>
<circle cx="150.8" cy="133" r=".4"/>
<circle cx="156.8" cy="125" r=".4"/>
<circle cx="162.2" cy="125.9" r=".4"/>
</g>
<g fill="none" stroke="#f0f0f0" stroke-width=".8">
<path d="M145.4 98.7v.5M146.7 98.7v.5M147.9 98.7v.5M184.9 98.7v.5M186.2 98.7v.5M187.4 98.7v.5M188.7 98.7v.5M189.9 98.7v.5M137.8 117.4h.5M137.8 118.6h.5M137.8 119.9h.5M137.8 109.1h.5"/>
<path d="M137.8 110.3h.5M137.8 111.6h.5M137.8 121.1h.5M137.8 122.4h.5M137.8 128.3h.5M137.8 129.5h.5M137.8 130.8h.5M137.8 132h.5M137.8 133.3h.5M137.7 141.1h.5M137.7 142.4h.5M137.7 143.6h.5"/>
<path d="M143.5 141.1h.5M143.5 142.4h.5M143.5 143.6h.5M148.8 149.9v.5M150.1 149.9v.5M151.3 149.9v.5M157 149.9v.5M158.3 149.9v.5M159.5 149.9v.5"/>
</g>
<path d="M173.7 98v.7M180.3 98v.7" fill="none" stroke="#f0f0f0" stroke-width=".9"/>
<g fill="none" stroke="#f0f0f0" stroke-width=".5">
<path d="M138.1 117.4h13.6l.8 .7v1.3M138.1 118.6h13.5M156 117.1l-3.3 3.3h-12.7l-.7 .7h-1.2M159.8 113v2.7l10.1 10h2.1l1.4-1.3M162 113v3.9l8 8h.2M163.1 113v3.8l7.1 7.1M164.2 113v3.9l5.6 5.5h2.7l.9 1M146.4 126l.5 .5h8.1l.4 .4h2.8M147.7 123.2h8.3M154 127.5l3 3.1M155.8 125.7v-1l1-1h4.5l1.8 1.8v1.8l-.6 .6h-.3l-6.3 6.3h-5.1M156.8 125h4.5l.9 .9"/>
<path d="M162.2 126.9h-1.5l-6.1 6.1h-3.8M163.9 130v.4l-13.5 13.6v.3M164.5 129.2l.3 .3v1.6l-14.1 14M165.7 129.1v5l-10.1 10.1M167 129.3l-.1 .1v6.1l-7.2 7.1v1.6M167.7 130.3v11.4l-2.5 2.6M168.7 127.4h-3.5l-15 15h-12.3M169.2 126.4h-4.1l-14.7 14.7h-12.5M192.9 122.8h-16.3l-5.6 5.6h-1.6M148.5 144.3l.9 .8"/>
</g>
<g fill="#fff" stroke="#fff" stroke-width=".13">
<circle cx="191.1" cy="119.5" r=".2"/>
<circle cx="163.8" cy="143" r=".2"/>
<circle cx="146.6" cy="136" r=".2"/>
<circle cx="185.5" cy="117.1" r=".2"/>
<circle cx="176" cy="121.1" r=".2"/>
<circle cx="184.1" cy="128.2" r=".2"/>
<circle cx="171" cy="117.2" r=".2"/>
<circle cx="186.9" cy="143.3" r=".2"/>
<circle cx="181.7" cy="136.2" r=".2"/>
<circle cx="184.1" cy="132" r=".2"/>
<circle cx="177.7" cy="134.3" r=".2"/>
<circle cx="191.3" cy="107.8" r=".2"/>
<circle cx="174.7" cy="128.8" r=".2"/>
<circle cx="181.9" cy="144.9" r=".2"/>
<circle cx="142.4" cy="127" r=".2"/>
<circle cx="160.4" cy="137.4" r=".2"/>
<circle cx="181.7" cy="134.3" r=".2"/>
<circle cx="183.6" cy="144.9" r=".2"/>
<circle cx="179.1" cy="117.3" r=".2"/>
<circle cx="187.9" cy="109.3" r=".2"/>
<circle cx="184.1" cy="130.1" r=".2"/>
<circle cx="174.6" cy="145.3" r=".2"/>
<circle cx="164.8" cy="140.1" r=".2"/>
<circle cx="177.7" cy="136.2" r=".2"/>
<circle cx="173.6" cy="134" r=".2"/>
<circle cx="146.1" cy="122.3" r=".2"/>
<circle cx="166.1" cy="141.1" r=".2"/>
<circle cx="163.1" cy="142" r=".2"/>
<circle cx="188.5" cy="117.1" r=".2"/>
<circle cx="177.4" cy="111.2" r=".2"/>
<circle cx="182.9" cy="119.5" r=".2"/>
<circle cx="162" cy="142" r=".2"/>
<circle cx="158.7" cy="113" r=".2"/>
<circle cx="157.7" cy="131.2" r=".2"/>
<circle cx="177.7" cy="132.5" r=".2"/>
<circle cx="169" cy="136.3" r=".2"/>
<circle cx="192.9" cy="112.6" r=".2"/>
<circle cx="157" cy="118.9" r=".2"/>
<circle cx="157.9" cy="139.8" r=".2"/>
<circle cx="170.3" cy="129.9" r=".2"/>
<circle cx="142.4" cy="136" r=".2"/>
<circle cx="146.9" cy="124.1" r=".2"/>
<circle cx="185.8" cy="138.8" r=".2"/>
<circle cx="174.2" cy="111.1" r=".2"/>
<circle cx="161.5" cy="136.3" r=".2"/>
<circle cx="174.7" cy="121.1" r=".2"/>
<circle cx="172.3" cy="117.2" r=".2"/>
<circle cx="182.2" cy="117.3" r=".2"/>
<circle cx="172.4" cy="145.3" r=".2"/>
<circle cx="178.6" cy="104.4" r=".2"/>
<circle cx="178.1" cy="128.5" r=".2"/>
<circle cx="184.1" cy="135.8" r=".2"/>
<circle cx="154.4" cy="143.3" r=".2"/>
<circle cx="175.1" cy="134.7" r=".2"/>
<circle cx="177.7" cy="130.7" r=".2"/>
<circle cx="176.6" cy="118.4" r=".2"/>
<circle cx="161.6" cy="145.9" r=".2"/>
<circle cx="175.1" cy="133.3" r=".2"/>
<circle cx="175.1" cy="131.9" r=".2"/>
<circle cx="184.1" cy="133.9" r=".2"/>
<circle cx="190.2" cy="109.2" r=".2"/>
<circle cx="148.3" cy="136" r=".2"/>
<circle cx="169.9" cy="144.3" r=".2"/>
<circle cx="174.2" cy="114.7" r=".2"/>
<circle cx="177.4" cy="116.5" r=".2"/>
<circle cx="192" cy="109" r=".2"/>
<circle cx="185.8" cy="127.4" r=".2"/>
<circle cx="183.6" cy="101.8" r=".2"/>
<circle cx="189.9" cy="107.8" r=".2"/>
<circle cx="188.4" cy="119.5" r=".2"/>
<circle cx="173.1" cy="147.4" r=".2"/>
<circle cx="142.4" cy="134.2" r=".2"/>
<circle cx="159.2" cy="138.6" r=".2"/>
<circle cx="142.4" cy="130.6" r=".2"/>
<circle cx="142.4" cy="132.4" r=".2"/>
<circle cx="184.1" cy="126.4" r=".2"/>
<circle cx="188.3" cy="104.9" r=".2"/>
<circle cx="153.5" cy="136" r=".2"/>
<circle cx="173.4" cy="121.1" r=".2"/>
<circle cx="191.6" cy="115.7" r=".2"/>
<circle cx="169.9" cy="142.6" r=".2"/>
<circle cx="173.6" cy="117.2" r=".2"/>
<circle cx="177.4" cy="107.6" r=".2"/>
<circle cx="185.9" cy="104.9" r=".2"/>
<circle cx="157" cy="129.3" r=".2"/>
<circle cx="156.8" cy="141" r=".2"/>
<circle cx="150.1" cy="136" r=".2"/>
<circle cx="187.1" cy="104.9" r=".2"/>
<circle cx="178.7" cy="125.7" r=".2"/>
<circle cx="142.2" cy="122.3" r=".2"/>
<circle cx="181.9" cy="146.9" r=".2"/>
<circle cx="192.9" cy="114.5" r=".2"/>
<circle cx="185.6" cy="141" r=".2"/>
<circle cx="173.5" cy="145.3" r=".2"/>
<circle cx="153.9" cy="121.8" r=".2"/>
<circle cx="177.4" cy="109.4" r=".2"/>
<circle cx="174.7" cy="146.7" r=".2"/>
<circle cx="169.1" cy="129.9" r=".2"/>
<circle cx="152.7" cy="124.1" r=".2"/>
<circle cx="176.6" cy="120" r=".2"/>
<circle cx="155.5" cy="118.9" r=".2"/>
<circle cx="144.2" cy="122.3" r=".2"/>
<circle cx="183.6" cy="104" r=".2"/>
<circle cx="184.6" cy="104" r=".2"/>
<circle cx="185.6" cy="119.5" r=".2"/>
<circle cx="181.7" cy="130.7" r=".2"/>
<circle cx="181.7" cy="132.5" r=".2"/>
<circle cx="174.2" cy="113" r=".2"/>
<circle cx="151.8" cy="136" r=".2"/>
<circle cx="165.1" cy="136" r=".2"/>
<circle cx="177.4" cy="113" r=".2"/>
<circle cx="193.9" cy="119.5" r=".2"/>
<circle cx="180.2" cy="119.5" r=".2"/>
<circle cx="184.2" cy="138.8" r=".2"/>
<circle cx="177.4" cy="114.7" r=".2"/>
<circle cx="152.5" cy="121.8" r=".2"/>
<circle cx="157" cy="120.4" r=".2"/>
<circle cx="179.9" cy="112.8" r=".2"/>
<circle cx="172.1" cy="120.9" r=".2"/>
<circle cx="178.9" cy="112.8" r=".2"/>
<circle cx="178.9" cy="114.8" r=".2"/>
<circle cx="177.4" cy="125.3" r=".2"/>
<circle cx="189.8" cy="144.8" r=".2"/>
<circle cx="162.4" cy="135.1" r=".2"/>
<circle cx="189.1" cy="114.8" r=".2"/>
<circle cx="179.9" cy="113.8" r=".2"/>
<circle cx="187" cy="115.8" r=".2"/>
<circle cx="179.9" cy="126.3" r=".2"/>
<circle cx="185" cy="114.8" r=".2"/>
<circle cx="173.6" cy="132.2" r=".2"/>
<circle cx="184" cy="114.8" r=".2"/>
<circle cx="185" cy="115.8" r=".2"/>
<circle cx="188" cy="114.8" r=".2"/>
<circle cx="160.9" cy="113" r=".2"/>
<circle cx="157.8" cy="128.2" r=".2"/>
<circle cx="147.1" cy="127.9" r=".2"/>
<circle cx="186" cy="115.8" r=".2"/>
<circle cx="144" cy="134.2" r=".2"/>
<circle cx="180.9" cy="115.8" r=".2"/>
<circle cx="183" cy="114.8" r=".2"/>
<circle cx="179.9" cy="111.8" r=".2"/>
<circle cx="148.1" cy="121.8" r=".2"/>
<circle cx="178.9" cy="111.8" r=".2"/>
<circle cx="179.9" cy="115.8" r=".2"/>
<circle cx="174.7" cy="130.5" r=".2"/>
<circle cx="179.2" cy="145" r=".2"/>
<circle cx="174.7" cy="116.9" r=".2"/>
<circle cx="186" cy="114.8" r=".2"/>
<circle cx="181.9" cy="114.8" r=".2"/>
<circle cx="183" cy="115.8" r=".2"/>
<circle cx="180.9" cy="114.8" r=".2"/>
<circle cx="178.9" cy="115.8" r=".2"/>
<circle cx="188" cy="115.8" r=".2"/>
<circle cx="161.3" cy="120.4" r=".2"/>
<circle cx="181.9" cy="115.8" r=".2"/>
<circle cx="184" cy="115.8" r=".2"/>
<circle cx="187" cy="114.8" r=".2"/>
<circle cx="151.2" cy="127.9" r=".2"/>
<circle cx="189.1" cy="115.8" r=".2"/>
<circle cx="178.9" cy="113.8" r=".2"/>
<circle cx="179.9" cy="114.8" r=".2"/>
<circle cx="165.2" cy="144.3" r=".2"/>
<circle cx="167.7" cy="130.3" r=".2"/>
<circle cx="195.4" cy="113.3" r=".2"/>
<circle cx="196.4" cy="109.2" r=".2"/>
<circle cx="194.4" cy="111.2" r=".2"/>
<circle cx="192" cy="118.2" r=".2"/>
<circle cx="195.4" cy="109.2" r=".2"/>
<circle cx="194.4" cy="110.2" r=".2"/>
<circle cx="195.4" cy="111.2" r=".2"/>
<circle cx="196.4" cy="110.2" r=".2"/>
<circle cx="195.4" cy="112.3" r=".2"/>
<circle cx="196.4" cy="113.3" r=".2"/>
<circle cx="194.4" cy="112.3" r=".2"/>
<circle cx="194.4" cy="109.2" r=".2"/>
<circle cx="196.4" cy="111.2" r=".2"/>
<circle cx="196.4" cy="112.3" r=".2"/>
<circle cx="194.4" cy="113.3" r=".2"/>
<circle cx="195.4" cy="110.2" r=".2"/>
<circle cx="170.3" cy="104.6" r=".2"/>
<circle cx="170.3" cy="102.6" r=".2"/>
<circle cx="171.3" cy="101.8" r=".2"/>
<circle cx="172.3" cy="104.6" r=".2"/>
<circle cx="170.3" cy="103.6" r=".2"/>
<circle cx="171.3" cy="104.6" r=".2"/>
<circle cx="172.3" cy="101.8" r=".2"/>
<circle cx="164.2" cy="113" r=".2"/>
<circle cx="173.4" cy="123.4" r=".2"/>
<circle cx="163.1" cy="113" r=".2"/>
<circle cx="170.2" cy="123.9" r=".2"/>
<circle cx="162" cy="113" r=".2"/>
<circle cx="170.2" cy="124.9" r=".2"/>
<circle cx="173.4" cy="124.4" r=".2"/>
<circle cx="159.8" cy="113" r=".2"/>
<circle cx="169.4" cy="128.4" r=".2"/>
<circle cx="152.5" cy="119.4" r=".2"/>
<circle cx="151.6" cy="118.6" r=".2"/>
<circle cx="156" cy="117.1" r=".2"/>
<circle cx="169.2" cy="126.4" r=".2"/>
<circle cx="168.7" cy="127.4" r=".2"/>
<circle cx="155.6" cy="144.2" r=".2"/>
<circle cx="165.7" cy="129.1" r=".2"/>
<circle cx="159.7" cy="144.2" r=".2"/>
<circle cx="167" cy="129.3" r=".2"/>
<circle cx="148.5" cy="144.3" r=".2"/>
<circle cx="164.5" cy="129.2" r=".2"/>
<circle cx="163.9" cy="130" r=".2"/>
<circle cx="150.4" cy="144.3" r=".2"/>
<circle cx="158.2" cy="126.9" r=".2"/>
<circle cx="146.4" cy="126" r=".2"/>
<circle cx="156" cy="123.2" r=".2"/>
<circle cx="147.7" cy="123.2" r=".2"/>
<circle cx="150.8" cy="134.2" r=".2"/>
<circle cx="162.2" cy="127.9" r=".2"/>
<circle cx="155.8" cy="125.7" r=".2"/>
<circle cx="162.2" cy="126.9" r=".2"/>
<circle cx="154" cy="127.5" r=".2"/>
<circle cx="150.8" cy="133" r=".2"/>
<circle cx="156.8" cy="125" r=".2"/>
<circle cx="162.2" cy="125.9" r=".2"/>
<circle cx="136.6" cy="149.2" r=".25"/>
<circle cx="137.3" cy="150.9" r=".25"/>
<circle cx="141.4" cy="149.2" r=".25"/>
<circle cx="139" cy="146.8" r=".25"/>
<circle cx="137.3" cy="147.6" r=".25"/>
<circle cx="139" cy="151.6" r=".25"/>
<circle cx="140.7" cy="150.9" r=".25"/>
<circle cx="139" cy="149.2" r="1.6"/>
<circle cx="140.7" cy="147.6" r=".25"/>
<circle cx="170.3" cy="151.1" r=".55"/>
<circle cx="163.8" cy="151.1" r=".55"/>
<circle cx="170.3" cy="146.6" r=".55"/>
<circle cx="163.8" cy="146.6" r=".55"/>
<circle cx="147.6" cy="150.2" r=".25"/>
<circle cx="148.8" cy="150.2" r=".25"/>
<circle cx="150.1" cy="150.2" r=".25"/>
<circle cx="151.3" cy="150.2" r=".25"/>
<circle cx="155.8" cy="150.2" r=".25"/>
<circle cx="157" cy="150.2" r=".25"/>
<circle cx="158.3" cy="150.2" r=".25"/>
<circle cx="159.5" cy="150.2" r=".25"/>
<circle cx="143.7" cy="139.9" r=".25"/>
<circle cx="143.7" cy="141.1" r=".25"/>
<circle cx="143.7" cy="142.4" r=".25"/>
<circle cx="143.7" cy="143.6" r=".25"/>
<circle cx="137.9" cy="139.9" r=".25"/>
<circle cx="137.9" cy="141.1" r=".25"/>
<circle cx="137.9" cy="142.4" r=".25"/>
<circle cx="137.9" cy="143.6" r=".25"/>
<circle cx="138.1" cy="116.1" r=".25"/>
<circle cx="138.1" cy="117.4" r=".25"/>
<circle cx="138.1" cy="118.6" r=".25"/>
<circle cx="138.1" cy="119.9" r=".25"/>
<circle cx="138.1" cy="121.1" r=".25"/>
<circle cx="138.1" cy="122.4" r=".25"/>
<circle cx="149.2" cy="99" r=".25"/>
<circle cx="147.9" cy="99" r=".25"/>
<circle cx="146.7" cy="99" r=".25"/>
<circle cx="145.4" cy="99" r=".25"/>
<circle cx="195.5" cy="143.1" r=".5"/>
<circle cx="198" cy="143.1" r=".5"/>
<circle cx="195.5" cy="140.6" r=".5"/>
<circle cx="198" cy="140.6" r=".5"/>
<circle cx="195.5" cy="138" r=".5"/>
<circle cx="198" cy="138" r=".5"/>
<circle cx="195.5" cy="135.5" r=".5"/>
<circle cx="198" cy="135.5" r=".5"/>
<circle cx="195.5" cy="132.9" r=".5"/>
<circle cx="198" cy="132.9" r=".5"/>
<circle cx="195.5" cy="130.4" r=".5"/>
<circle cx="198" cy="130.4" r=".5"/>
<circle cx="195.5" cy="127.9" r=".5"/>
<circle cx="198" cy="127.9" r=".5"/>
<circle cx="195.5" cy="125.3" r=".5"/>
<circle cx="198" cy="125.3" r=".5"/>
<circle cx="195.5" cy="122.8" r=".5"/>
<circle cx="198" cy="122.8" r=".5"/>
<circle cx="178.4" cy="150.1" r=".45"/>
<circle cx="175.4" cy="150.1" r=".45"/>
<circle cx="195.3" cy="98.6" r=".25"/>
<circle cx="197" cy="102.6" r=".25"/>
<circle cx="197" cy="97.8" r=".25"/>
<circle cx="198.7" cy="98.6" r=".25"/>
<circle cx="198.7" cy="101.9" r=".25"/>
<circle cx="197" cy="100.2" r="1.6"/>
<circle cx="194.6" cy="100.2" r=".25"/>
<circle cx="199.4" cy="100.2" r=".25"/>
<circle cx="195.3" cy="101.9" r=".25"/>
<circle cx="138.1" cy="107.8" r=".25"/>
<circle cx="138.1" cy="109.1" r=".25"/>
<circle cx="138.1" cy="110.3" r=".25"/>
<circle cx="138.1" cy="111.6" r=".25"/>
<circle cx="197" cy="149.2" r="1.6"/>
<circle cx="197" cy="151.6" r=".25"/>
<circle cx="194.6" cy="149.2" r=".25"/>
<circle cx="195.3" cy="150.9" r=".25"/>
<circle cx="198.7" cy="150.9" r=".25"/>
<circle cx="195.3" cy="147.6" r=".25"/>
<circle cx="199.4" cy="149.2" r=".25"/>
<circle cx="197" cy="146.8" r=".25"/>
<circle cx="198.7" cy="147.6" r=".25"/>
<circle cx="138.1" cy="127" r=".25"/>
<circle cx="138.1" cy="128.3" r=".25"/>
<circle cx="138.1" cy="129.5" r=".25"/>
<circle cx="138.1" cy="130.8" r=".25"/>
<circle cx="138.1" cy="132" r=".25"/>
<circle cx="138.1" cy="133.3" r=".25"/>
<circle cx="191" cy="150" r=".5"/>
<circle cx="188.4" cy="150" r=".5"/>
<circle cx="185.9" cy="150" r=".5"/>
<circle cx="183.3" cy="150" r=".5"/>
<circle cx="191.2" cy="99" r=".25"/>
<circle cx="189.9" cy="99" r=".25"/>
<circle cx="188.7" cy="99" r=".25"/>
<circle cx="187.4" cy="99" r=".25"/>
<circle cx="186.2" cy="99" r=".25"/>
<circle cx="184.9" cy="99" r=".25"/>
<circle cx="192.9" cy="122.8" r=".5"/>
<circle cx="192.9" cy="125.3" r=".5"/>
<circle cx="192.9" cy="127.9" r=".5"/>
<circle cx="192.9" cy="130.4" r=".5"/>
<circle cx="192.9" cy="133" r=".5"/>
<circle cx="192.9" cy="135.5" r=".5"/>
<circle cx="192.9" cy="138" r=".5"/>
<circle cx="192.9" cy="140.6" r=".5"/>
<circle cx="192.9" cy="143.1" r=".5"/>
<circle cx="136.6" cy="100.2" r=".25"/>
<circle cx="141.4" cy="100.2" r=".25"/>
<circle cx="137.3" cy="98.6" r=".25"/>
<circle cx="140.7" cy="101.9" r=".25"/>
<circle cx="139" cy="97.8" r=".25"/>
<circle cx="140.7" cy="98.6" r=".25"/>
<circle cx="139" cy="102.6" r=".25"/>
<circle cx="137.3" cy="101.9" r=".25"/>
<circle cx="139" cy="100.2" r="1.6"/>
<circle cx="165" cy="100.5" r=".45"/>
<circle cx="157" cy="100.5" r=".45"/>
</g>
<path d="M173.7 98v.7M180.3 98v.7" fill="none" stroke="#fff" stroke-width=".5"/>
<g fill="none" stroke="#000" stroke-width=".13">
<path d="M144.2 108.9l.4 .6M144.2 117.2l.4 .5M144.2 118.4l.5 .6M144.2 110.2l.5 .5M144.6 108.9l-.4 .6M144.6 117.2l-.4 .5M144.7 118.4l-.5 .6M144.7 110.2l-.5 .5M145.2 119.7h-.2l-.1 .1 .1 .1 .2 .1v.2h-.3M146.5 100.2l.5 .4M147 100.2l-.5 .4M147.7 100.2l.6 .4"/>
<path d="M148.3 100.2l-.6 .4M144.2 128.1l.4 .6M144.2 129.4l.5 .5M144.6 128.1l-.4 .6M144.7 129.4l-.5 .5M145 121l-.1-.1-.2 .2 .1 .1h.2v.2h-.3M149.2 144.1v.5l-.6-.5-.2 .2v.3M149.6 144.6v-.5l.3 .3 .1-.3h.3l.1 .2-.1 .3M157.4 144.3h-.8l.2 .3M157.4 144.1v.5M157.9 144.2a.47 .47 0 0 1 .8 .2 .45 .45 0 0 1-.8-.1z"/>
</g>
<path d="M136.2 97.4a4 4 0 0 1 2.8-1.2h58a4 4 0 0 1 4 4v49a4 4 0 0 1-4 4h-58a4 4 0 0 1-4-4v-49a4 4 0 0 1 1.2-2.8z" fill="none" stroke="#575757" stroke-width=".2"/>
<use href="#words"/>
</svg>
